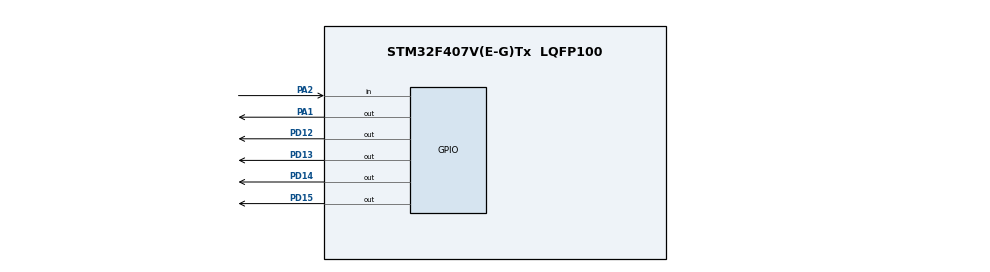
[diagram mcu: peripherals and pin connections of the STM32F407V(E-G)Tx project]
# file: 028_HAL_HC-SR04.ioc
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Mcu.Family=STM32F4
Mcu.Name=STM32F407V(E-G)Tx
Mcu.Package=LQFP100
NVIC.PriorityGroup=NVIC_PRIORITYGROUP_0
PA1.Signal=GPIO_Output
PA2.Signal=GPIO_Input
PD12.Signal=GPIO_Output
PD13.Signal=GPIO_Output
PD14.Signal=GPIO_Output
PD15.Signal=GPIO_Output
PH0-OSC_IN.Mode=HSE-External-Oscillator
PH0-OSC_IN.Signal=RCC_OSC_IN
PH1-OSC_OUT.Mode=HSE-External-Oscillator
PH1-OSC_OUT.Signal=RCC_OSC_OUT
ProjectManager.HeapSize=0x200
ProjectManager.StackSize=0x400
ProjectManager.TargetToolchain=STM32CubeIDE
RCC.48MHZClocksFreq_Value=24000000
RCC.AHBFreq_Value=84000000
RCC.APB1CLKDivider=RCC_HCLK_DIV4
RCC.APB1Freq_Value=21000000
RCC.APB1TimFreq_Value=42000000
RCC.APB2CLKDivider=RCC_HCLK_DIV2
RCC.APB2Freq_Value=42000000
RCC.APB2TimFreq_Value=84000000
RCC.CortexFreq_Value=84000000
RCC.HCLKFreq_Value=84000000
RCC.HSE_VALUE=8000000
RCC.HSI_VALUE=16000000
RCC.LSE_VALUE=32768
RCC.PLLM=8
RCC.PLLN=168
RCC.PLLQ=7
RCC.PLLSourceVirtual=RCC_PLLSOURCE_HSE
RCC.SYSCLKFreq_VALUE=84000000
RCC.SYSCLKSource=RCC_SYSCLKSOURCE_PLLCLK
RCC.VCOOutputFreq_Value=168000000
board=STM32F407G-DISC1

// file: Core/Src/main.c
/* USER CODE BEGIN Header */
/**
  ******************************************************************************
  * @file           : main.c
  * @brief          : Main program body
  ******************************************************************************
  * @attention
  *
  * Copyright (c) 2023 STMicroelectronics.
  * All rights reserved.
  *
  * This software is licensed under terms that can be found in the LICENSE file
  * in the root directory of this software component.
  * If no LICENSE file comes with this software, it is provided AS-IS.
  *
  ******************************************************************************
  */
/* USER CODE END Header */
#include "main.h"

/* USER CODE BEGIN Includes */
#include "dwt_stm32_delay.h"
/* USER CODE END Includes */

void SystemClock_Config(void);
static void MX_GPIO_Init(void);

/* USER CODE BEGIN 0 */

uint32_t sensor_time;
uint16_t distance;

uint32_t Read_HCSR04()
{
	uint32_t local_time = 0;

	HAL_GPIO_WritePin(GPIOA, GPIO_PIN_1, GPIO_PIN_SET);		// pull the trig pin high
	DWT_Delay_us(10);										// wait for 10 us
	HAL_GPIO_WritePin(GPIOA, GPIO_PIN_1, GPIO_PIN_RESET);	// pull the trig pin low

	// wait for the echo pin to go high

	while(!(HAL_GPIO_ReadPin(GPIOA, GPIO_PIN_2)));

	while(HAL_GPIO_ReadPin(GPIOA, GPIO_PIN_2))				// while the pin is high
	{
		local_time++;										// increment local time
		DWT_Delay_us(1);									// every 1 us
	}

	return local_time * 2;
}

/* USER CODE END 0 */

int main(void)
{

  /* MCU Configuration--------------------------------------------------------*/

  /* Reset of all peripherals, Initializes the Flash interface and the Systick. */
  HAL_Init();

  /* Configure the system clock */
  SystemClock_Config();

  /* Initialize all configured peripherals */
  MX_GPIO_Init();
  /* USER CODE BEGIN 2 */
  DWT_Delay_Init();
  /* USER CODE END 2 */

  /* Infinite loop */
  while (1)
  {

    /* USER CODE BEGIN 3 */

	  sensor_time = Read_HCSR04();			// get the high time
	  distance = sensor_time * .034 / 2;	// user the formula to get the distance

	  if(distance <= 4)
		  HAL_GPIO_WritePin(GPIOD, GPIO_PIN_All, GPIO_PIN_SET);
	  else if(distance > 4 && distance <= 6)
	  {
		  HAL_GPIO_WritePin(GPIOD, GPIO_PIN_12 | GPIO_PIN_13 | GPIO_PIN_14, GPIO_PIN_SET);
		  HAL_GPIO_WritePin(GPIOD, GPIO_PIN_15, GPIO_PIN_RESET);
	  }
	  else if(distance > 6 && distance <= 8)
	  {
		  HAL_GPIO_WritePin(GPIOD, GPIO_PIN_12 | GPIO_PIN_13, GPIO_PIN_SET);
		  HAL_GPIO_WritePin(GPIOD, GPIO_PIN_14 | GPIO_PIN_15, GPIO_PIN_RESET);
	  }
	  else if(distance > 8 && distance <= 10)
	  {
		  HAL_GPIO_WritePin(GPIOD, GPIO_PIN_12, GPIO_PIN_SET);
		  HAL_GPIO_WritePin(GPIOD, GPIO_PIN_13 | GPIO_PIN_14 | GPIO_PIN_15, GPIO_PIN_RESET);
	  }
	  else
	  {
		  HAL_GPIO_WritePin(GPIOD, GPIO_PIN_All, GPIO_PIN_RESET);
	  }
  }
  /* USER CODE END 3 */
}

void SystemClock_Config(void)
{
  RCC_OscInitTypeDef RCC_OscInitStruct = {0};
  RCC_ClkInitTypeDef RCC_ClkInitStruct = {0};

  /** Configure the main internal regulator output voltage
  */
  __HAL_RCC_PWR_CLK_ENABLE();
  __HAL_PWR_VOLTAGESCALING_CONFIG(PWR_REGULATOR_VOLTAGE_SCALE1);
  /** Initializes the CPU, AHB and APB busses clocks
  */
  RCC_OscInitStruct.OscillatorType = RCC_OSCILLATORTYPE_HSE;
  RCC_OscInitStruct.HSEState = RCC_HSE_ON;
  RCC_OscInitStruct.PLL.PLLState = RCC_PLL_ON;
  RCC_OscInitStruct.PLL.PLLSource = RCC_PLLSOURCE_HSE;
  RCC_OscInitStruct.PLL.PLLM = 4;
  RCC_OscInitStruct.PLL.PLLN = 168;
  RCC_OscInitStruct.PLL.PLLP = RCC_PLLP_DIV2;
  RCC_OscInitStruct.PLL.PLLQ = 4;
  if (HAL_RCC_OscConfig(&RCC_OscInitStruct) != HAL_OK)
  {
    Error_Handler();
  }
  /** Initializes the CPU, AHB and APB busses clocks
  */
  RCC_ClkInitStruct.ClockType = RCC_CLOCKTYPE_HCLK|RCC_CLOCKTYPE_SYSCLK
                              |RCC_CLOCKTYPE_PCLK1|RCC_CLOCKTYPE_PCLK2;
  RCC_ClkInitStruct.SYSCLKSource = RCC_SYSCLKSOURCE_PLLCLK;
  RCC_ClkInitStruct.AHBCLKDivider = RCC_SYSCLK_DIV1;
  RCC_ClkInitStruct.APB1CLKDivider = RCC_HCLK_DIV4;
  RCC_ClkInitStruct.APB2CLKDivider = RCC_HCLK_DIV2;

  if (HAL_RCC_ClockConfig(&RCC_ClkInitStruct, FLASH_LATENCY_5) != HAL_OK)
  {
    Error_Handler();
  }
}

static void MX_GPIO_Init(void)
{
  GPIO_InitTypeDef GPIO_InitStruct = {0};

  /* GPIO Ports Clock Enable */
  __HAL_RCC_GPIOH_CLK_ENABLE();
  __HAL_RCC_GPIOA_CLK_ENABLE();
  __HAL_RCC_GPIOD_CLK_ENABLE();

  /*Configure GPIO pin Output Level */
  HAL_GPIO_WritePin(GPIOA, GPIO_PIN_1, GPIO_PIN_RESET);

  /*Configure GPIO pin Output Level */
  HAL_GPIO_WritePin(GPIOD, GPIO_PIN_12|GPIO_PIN_13|GPIO_PIN_14|GPIO_PIN_15, GPIO_PIN_RESET);

  /*Configure GPIO pin : PA1 */
  GPIO_InitStruct.Pin = GPIO_PIN_1;
  GPIO_InitStruct.Mode = GPIO_MODE_OUTPUT_PP;
  GPIO_InitStruct.Pull = GPIO_NOPULL;
  GPIO_InitStruct.Speed = GPIO_SPEED_FREQ_LOW;
  HAL_GPIO_Init(GPIOA, &GPIO_InitStruct);

  /*Configure GPIO pin : PA2 */
  GPIO_InitStruct.Pin = GPIO_PIN_2;
  GPIO_InitStruct.Mode = GPIO_MODE_INPUT;
  GPIO_InitStruct.Pull = GPIO_NOPULL;
  HAL_GPIO_Init(GPIOA, &GPIO_InitStruct);

  /*Configure GPIO pins : PD12 PD13 PD14 PD15 */
  GPIO_InitStruct.Pin = GPIO_PIN_12|GPIO_PIN_13|GPIO_PIN_14|GPIO_PIN_15;
  GPIO_InitStruct.Mode = GPIO_MODE_OUTPUT_PP;
  GPIO_InitStruct.Pull = GPIO_NOPULL;
  GPIO_InitStruct.Speed = GPIO_SPEED_FREQ_LOW;
  HAL_GPIO_Init(GPIOD, &GPIO_InitStruct);

}

void Error_Handler(void)
{
}

/************************ (C) COPYRIGHT STMicroelectronics *****END OF FILE****/
